! (c) 2009  Infineon Technologies AG, Munich
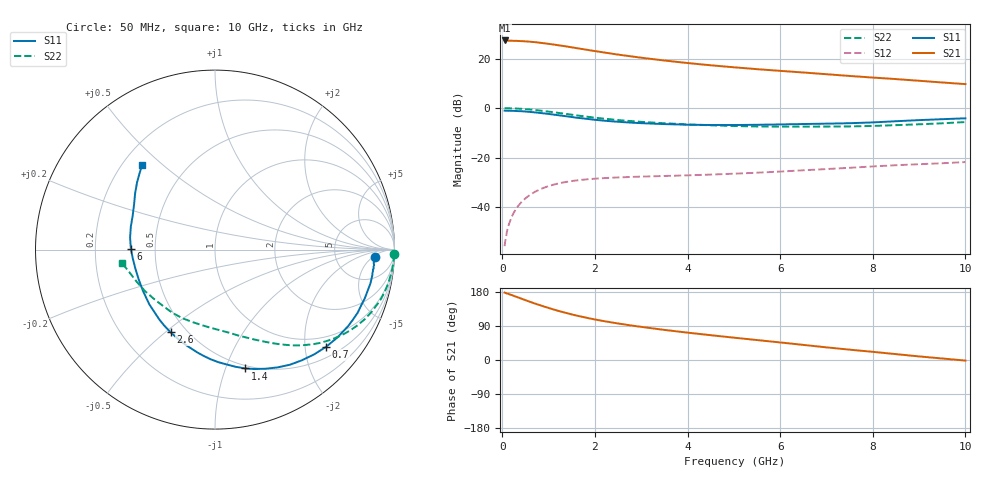
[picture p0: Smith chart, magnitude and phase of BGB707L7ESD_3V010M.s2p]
!  Infineon Technologies AG
!  BGB707L7ESD RU919007 w#7 Sample Build #08493 Teil Nr. 3
!  Vce = 3.0V, Ic = 10.0mA
!  DATUM: 30.06.2009 10:18:19
# GHz  S  MA  R  50
!f  S11  S21  S12  S22
!GHz  Mag  Ang  Mag  Ang  Mag  Ang  Mag  Ang
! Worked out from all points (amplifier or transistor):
!   52 points, 50 MHz to 10 GHz, reference 50 ohm
!   highest |S21| = 27.4 dB at 60 MHz (marker M1)
!   |S21| within 3 dB of that: start of sweep to 1.568 GHz
!   unconditionally stable (mu >= 1): 5.338 GHz to 9.494 GHz
!   at 130 MHz: K = 0.01, MSG = 37.7 dB, |S12| = -48.0 dB
!   at 1.4 GHz: K = 0.27, MSG = 27.4 dB, |S12| = -29.8 dB
!   at 10 GHz: K = 0.95, MSG = 15.8 dB, |S12| = -21.8 dB
!   lowest NFmin = 0.55 dB at 100 MHz
!   S11 on the Smith chart (normalised r, x): 50 MHz: 15, -6; 700 MHz: 0.74, -2.47; 1.4 GHz: 0.47, -1.17; 2.6 GHz: 0.41, -0.52; 6 GHz: 0.36, +0.01; 10 GHz: 0.28, +0.43
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0.05  0.8928 -2.8  23.09 177.8  0.001608 86.7  0.9968 -1.5
0.06  0.8901 -3.5  23.5 177.4  0.001963 84.2  0.997 -2.0
0.08  0.887 -4.8  23.12 176.3  0.002453 87.9  0.9972 -2.8
0.09  0.8909 -5.6  23.31 176.5  0.002745 87.6  0.9973 -3.2
0.2  0.8865 -12.2  23.25 171.5  0.006196 83.4  0.9918 -7.4
0.35  0.8714 -21.0  22.95 164.7  0.01066 78.2  0.9777 -12.8
0.5  0.8555 -29.9  22.55 158.0  0.01495 73.6  0.9564 -18.2
0.7  0.8226 -41.2  21.75 149.2  0.02014 67.3  0.92 -24.9
0.9  0.784 -51.9  20.63 141.1  0.02454 61.6  0.876 -31.1
1.1  0.7426 -62.1  19.49 133.5  0.02818 56.6  0.8286 -36.7
1.4  0.6828 -75.9  17.66 123.5  0.03234 50.5  0.7594 -44.0
1.8  0.6119 -92.2  15.36 112.0  0.03605 44.4  0.6773 -51.9
2.2  0.558 -106.3  13.42 102.5  0.0384 40.4  0.6126 -58.3
2.6  0.5227 -118.2  11.8 94.5  0.03996 38.0  0.5644 -63.9
3  0.4972 -128.8  10.51 87.4  0.04116 36.7  0.5285 -69.0
3.5  0.4764 -140.2  9.225 79.4  0.0424 36.1  0.4952 -75.0
4.5  0.4565 -158.8  7.386 65.5  0.04525 37.4  0.45 -86.6
5.5  0.461 -174.1  6.168 52.6  0.04941 39.8  0.4267 -100.5
6  0.4689 179.3  5.695 46.4  0.05209 41.0  0.4227 -107.9
7  0.4861 164.8  4.87 33.4  0.05853 42.0  0.4245 -124.3
8.5  0.5441 144.9  3.883 15.5  0.07006 41.0  0.4532 -149.3
10  0.6237 130.6  3.073 -1.6  0.08109 38.5  0.524 -172.0
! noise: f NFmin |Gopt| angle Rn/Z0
0.1  0.55  0.46  2  0.18
0.45  0.69  0.46  4  0.18
0.9  0.73  0.47  12  0.18
1.8  0.75  0.4  33  0.17
5  0.97  0.31  70  0.16
10  1.48  0.39  -123  0.14
